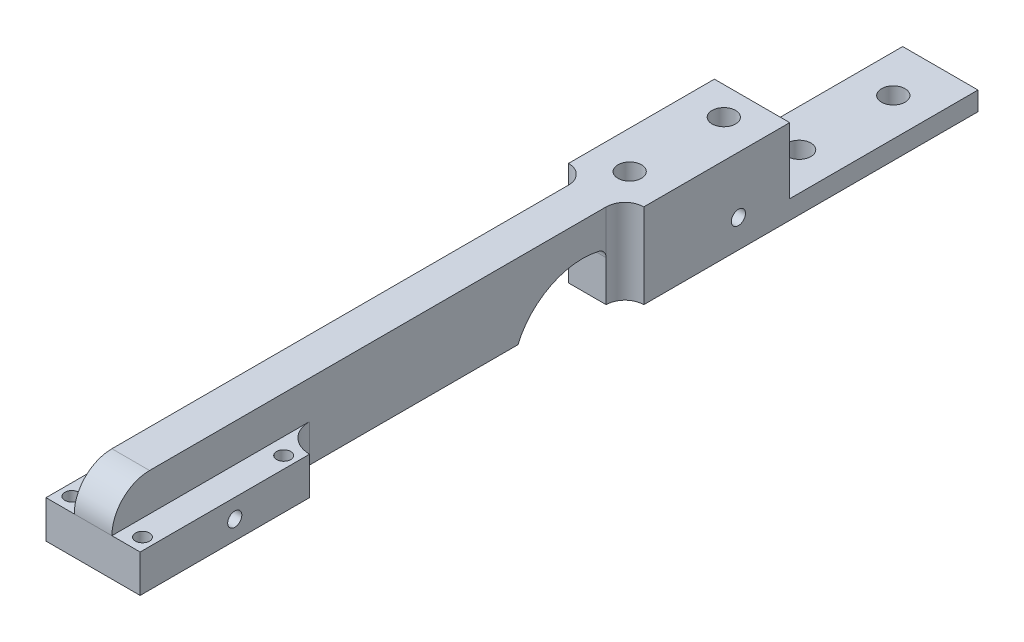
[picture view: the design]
ISO-10303-21;
HEADER;
FILE_DESCRIPTION(('STEP AP214'),'2;1');
FILE_NAME('part.step','',(''),(''),'','','');
FILE_SCHEMA(('AUTOMOTIVE_DESIGN { 1 0 10303 214 1 1 1 1 }'));
ENDSEC;
DATA;
#1=APPLICATION_CONTEXT('core data for automotive mechanical design processes');
#2=APPLICATION_PROTOCOL_DEFINITION('international standard','automotive_design',2000,#1);
#3=PRODUCT_CONTEXT('',#1,'mechanical');
#4=PRODUCT('Part','Part','',(#3));
#5=PRODUCT_RELATED_PRODUCT_CATEGORY('part','',(#4));
#6=PRODUCT_DEFINITION_FORMATION('','',#4);
#7=PRODUCT_DEFINITION_CONTEXT('part definition',#1,'design');
#8=PRODUCT_DEFINITION('design','',#6,#7);
#9=PRODUCT_DEFINITION_SHAPE('','',#8);
#10=(LENGTH_UNIT() NAMED_UNIT(*) SI_UNIT(.MILLI.,.METRE.));
#11=(NAMED_UNIT(*) PLANE_ANGLE_UNIT() SI_UNIT($,.RADIAN.));
#12=(NAMED_UNIT(*) SI_UNIT($,.STERADIAN.) SOLID_ANGLE_UNIT());
#13=UNCERTAINTY_MEASURE_WITH_UNIT(LENGTH_MEASURE(1.E-05),#10,'distance_accuracy_value','');
#14=(GEOMETRIC_REPRESENTATION_CONTEXT(3) GLOBAL_UNCERTAINTY_ASSIGNED_CONTEXT((#13)) GLOBAL_UNIT_ASSIGNED_CONTEXT((#10,
#11,#12)) REPRESENTATION_CONTEXT('',''));
#15=CARTESIAN_POINT('',(0.,0.,0.));
#16=DIRECTION('',(0.,0.,1.));
#17=DIRECTION('',(1.,0.,0.));
#18=AXIS2_PLACEMENT_3D('',#15,#16,#17);
#19=CARTESIAN_POINT('',(0.,0.,0.));
#20=DIRECTION('',(0.,0.,1.));
#21=DIRECTION('',(1.,0.,0.));
#22=AXIS2_PLACEMENT_3D('',#19,#20,#21);
#23=PLANE('',#22);
#24=DIRECTION('',(1.,0.,0.));
#25=VECTOR('',#24,1.);
#26=CARTESIAN_POINT('',(-8.,0.,0.));
#27=LINE('',#26,#25);
#28=CARTESIAN_POINT('',(-8.,0.,0.));
#29=VERTEX_POINT('',#28);
#30=CARTESIAN_POINT('',(8.,0.,0.));
#31=VERTEX_POINT('',#30);
#32=EDGE_CURVE('E338',#29,#31,#27,.T.);
#33=ORIENTED_EDGE('',*,*,#32,.F.);
#34=DIRECTION('',(0.,1.,0.));
#35=VECTOR('',#34,1.);
#36=CARTESIAN_POINT('',(-8.,-4.,0.));
#37=LINE('',#36,#35);
#38=CARTESIAN_POINT('',(-8.,14.,0.));
#39=VERTEX_POINT('',#38);
#40=EDGE_CURVE('E562',#29,#39,#37,.T.);
#41=ORIENTED_EDGE('',*,*,#40,.T.);
#42=DIRECTION('',(-1.,0.,0.));
#43=VECTOR('',#42,1.);
#44=CARTESIAN_POINT('',(4.,14.,0.));
#45=LINE('',#44,#43);
#46=CARTESIAN_POINT('',(8.,14.,0.));
#47=VERTEX_POINT('',#46);
#48=EDGE_CURVE('E549',#47,#39,#45,.T.);
#49=ORIENTED_EDGE('',*,*,#48,.F.);
#50=DIRECTION('',(0.,1.,0.));
#51=VECTOR('',#50,1.);
#52=CARTESIAN_POINT('',(8.,-4.,0.));
#53=LINE('',#52,#51);
#54=EDGE_CURVE('E359',#31,#47,#53,.T.);
#55=ORIENTED_EDGE('',*,*,#54,.F.);
#56=EDGE_LOOP('',(#33,#41,#49,#55));
#57=FACE_BOUND('',#56,.T.);
#58=ADVANCED_FACE('F33',(#57),#23,.F.);
#59=CARTESIAN_POINT('',(10.,-2.,140.));
#60=DIRECTION('',(0.,1.,0.));
#61=DIRECTION('',(-1.,0.,0.));
#62=AXIS2_PLACEMENT_3D('',#59,#60,#61);
#63=PLANE('',#62);
#64=DIRECTION('',(0.,0.,-1.));
#65=VECTOR('',#64,1.);
#66=CARTESIAN_POINT('',(-3.,-2.,79.));
#67=LINE('',#66,#65);
#68=CARTESIAN_POINT('',(-3.,-2.,79.));
#69=VERTEX_POINT('',#68);
#70=CARTESIAN_POINT('',(-3.,-2.,65.));
#71=VERTEX_POINT('',#70);
#72=EDGE_CURVE('E268',#69,#71,#67,.T.);
#73=ORIENTED_EDGE('',*,*,#72,.F.);
#74=CARTESIAN_POINT('',(0.,-2.,79.));
#75=DIRECTION('',(0.,-1.,0.));
#76=DIRECTION('',(1.,0.,0.));
#77=AXIS2_PLACEMENT_3D('',#74,#75,#76);
#78=CIRCLE('',#77,3.);
#79=CARTESIAN_POINT('',(3.,-2.,79.));
#80=VERTEX_POINT('',#79);
#81=EDGE_CURVE('E48',#80,#69,#78,.T.);
#82=ORIENTED_EDGE('',*,*,#81,.F.);
#83=DIRECTION('',(0.,0.,1.));
#84=VECTOR('',#83,1.);
#85=CARTESIAN_POINT('',(3.,-2.,79.));
#86=LINE('',#85,#84);
#87=CARTESIAN_POINT('',(3.,-2.,65.));
#88=VERTEX_POINT('',#87);
#89=EDGE_CURVE('E256',#88,#80,#86,.T.);
#90=ORIENTED_EDGE('',*,*,#89,.F.);
#91=CARTESIAN_POINT('',(0.,-2.,65.));
#92=DIRECTION('',(0.,-1.,0.));
#93=DIRECTION('',(1.,0.,0.));
#94=AXIS2_PLACEMENT_3D('',#91,#92,#93);
#95=CIRCLE('',#94,3.);
#96=EDGE_CURVE('E259',#71,#88,#95,.T.);
#97=ORIENTED_EDGE('',*,*,#96,.F.);
#98=EDGE_LOOP('',(#73,#82,#90,#97));
#99=FACE_BOUND('',#98,.T.);
#100=CARTESIAN_POINT('',(-7.49999999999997,-2.,107.));
#101=DIRECTION('',(0.,1.,0.));
#102=DIRECTION('',(-1.,0.,0.));
#103=AXIS2_PLACEMENT_3D('',#100,#101,#102);
#104=CIRCLE('',#103,1.5);
#105=CARTESIAN_POINT('',(-5.99999999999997,-2.,107.));
#106=VERTEX_POINT('',#105);
#107=CARTESIAN_POINT('',(-7.5,-2.,108.5));
#108=VERTEX_POINT('',#107);
#109=EDGE_CURVE('E323',#106,#108,#104,.T.);
#110=ORIENTED_EDGE('',*,*,#109,.T.);
#111=DIRECTION('',(0.,0.,-1.));
#112=VECTOR('',#111,1.);
#113=CARTESIAN_POINT('',(-7.5,-2.,137.));
#114=LINE('',#113,#112);
#115=CARTESIAN_POINT('',(-7.5,-2.,135.5));
#116=VERTEX_POINT('',#115);
#117=EDGE_CURVE('E275',#116,#108,#114,.T.);
#118=ORIENTED_EDGE('',*,*,#117,.F.);
#119=CARTESIAN_POINT('',(-7.5,-2.,137.));
#120=DIRECTION('',(0.,1.,0.));
#121=DIRECTION('',(-1.,0.,0.));
#122=AXIS2_PLACEMENT_3D('',#119,#120,#121);
#123=CIRCLE('',#122,1.5);
#124=CARTESIAN_POINT('',(-6.,-2.,137.));
#125=VERTEX_POINT('',#124);
#126=EDGE_CURVE('E317',#116,#125,#123,.T.);
#127=ORIENTED_EDGE('',*,*,#126,.T.);
#128=DIRECTION('',(-1.,0.,0.));
#129=VECTOR('',#128,1.);
#130=CARTESIAN_POINT('',(-7.5,-2.,137.));
#131=LINE('',#130,#129);
#132=CARTESIAN_POINT('',(6.,-2.,137.));
#133=VERTEX_POINT('',#132);
#134=EDGE_CURVE('E283',#133,#125,#131,.T.);
#135=ORIENTED_EDGE('',*,*,#134,.F.);
#136=CARTESIAN_POINT('',(7.5,-2.,137.));
#137=DIRECTION('',(0.,1.,0.));
#138=DIRECTION('',(-1.,0.,0.));
#139=AXIS2_PLACEMENT_3D('',#136,#137,#138);
#140=CIRCLE('',#139,1.5);
#141=CARTESIAN_POINT('',(7.5,-2.,135.5));
#142=VERTEX_POINT('',#141);
#143=EDGE_CURVE('E335',#133,#142,#140,.T.);
#144=ORIENTED_EDGE('',*,*,#143,.T.);
#145=DIRECTION('',(0.,0.,1.));
#146=VECTOR('',#145,1.);
#147=CARTESIAN_POINT('',(7.5,-2.,137.));
#148=LINE('',#147,#146);
#149=CARTESIAN_POINT('',(7.5,-2.,108.5));
#150=VERTEX_POINT('',#149);
#151=EDGE_CURVE('E294',#150,#142,#148,.T.);
#152=ORIENTED_EDGE('',*,*,#151,.F.);
#153=CARTESIAN_POINT('',(7.5,-2.,107.));
#154=DIRECTION('',(0.,1.,0.));
#155=DIRECTION('',(-1.,0.,0.));
#156=AXIS2_PLACEMENT_3D('',#153,#154,#155);
#157=CIRCLE('',#156,1.5);
#158=CARTESIAN_POINT('',(6.,-2.,107.));
#159=VERTEX_POINT('',#158);
#160=EDGE_CURVE('E329',#150,#159,#157,.T.);
#161=ORIENTED_EDGE('',*,*,#160,.T.);
#162=DIRECTION('',(1.,0.,0.));
#163=VECTOR('',#162,1.);
#164=CARTESIAN_POINT('',(-7.5,-2.,107.));
#165=LINE('',#164,#163);
#166=EDGE_CURVE('E292',#106,#159,#165,.T.);
#167=ORIENTED_EDGE('',*,*,#166,.F.);
#168=EDGE_LOOP('',(#110,#118,#127,#135,#144,#152,#161,#167));
#169=FACE_BOUND('',#168,.T.);
#170=DIRECTION('',(0.,0.,-1.));
#171=VECTOR('',#170,1.);
#172=CARTESIAN_POINT('',(-4.,-2.,0.));
#173=LINE('',#172,#171);
#174=CARTESIAN_POINT('',(-3.99999999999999,-2.,98.));
#175=VERTEX_POINT('',#174);
#176=CARTESIAN_POINT('',(-4.,-1.99999999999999,53.7477270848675));
#177=VERTEX_POINT('',#176);
#178=EDGE_CURVE('E528',#175,#177,#173,.T.);
#179=ORIENTED_EDGE('',*,*,#178,.T.);
#180=DIRECTION('',(1.,0.,0.));
#181=VECTOR('',#180,1.);
#182=CARTESIAN_POINT('',(-10.000025,-1.99999999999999,53.7477270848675));
#183=LINE('',#182,#181);
#184=CARTESIAN_POINT('',(4.,-1.99999999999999,53.7477270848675));
#185=VERTEX_POINT('',#184);
#186=EDGE_CURVE('E579',#177,#185,#183,.T.);
#187=ORIENTED_EDGE('',*,*,#186,.T.);
#188=DIRECTION('',(0.,0.,1.));
#189=VECTOR('',#188,1.);
#190=CARTESIAN_POINT('',(4.,-2.,0.));
#191=LINE('',#190,#189);
#192=CARTESIAN_POINT('',(4.00000000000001,-2.,98.));
#193=VERTEX_POINT('',#192);
#194=EDGE_CURVE('E518',#185,#193,#191,.T.);
#195=ORIENTED_EDGE('',*,*,#194,.T.);
#196=CARTESIAN_POINT('',(10.,-2.,98.));
#197=DIRECTION('',(0.,1.,0.));
#198=DIRECTION('',(0.,0.,1.));
#199=AXIS2_PLACEMENT_3D('',#196,#197,#198);
#200=CIRCLE('',#199,6.);
#201=CARTESIAN_POINT('',(10.,-2.,104.));
#202=VERTEX_POINT('',#201);
#203=EDGE_CURVE('E521',#193,#202,#200,.T.);
#204=ORIENTED_EDGE('',*,*,#203,.T.);
#205=DIRECTION('',(0.,0.,-1.));
#206=VECTOR('',#205,1.);
#207=CARTESIAN_POINT('',(10.,-2.,140.));
#208=LINE('',#207,#206);
#209=CARTESIAN_POINT('',(10.,-2.,140.));
#210=VERTEX_POINT('',#209);
#211=EDGE_CURVE('E500',#210,#202,#208,.T.);
#212=ORIENTED_EDGE('',*,*,#211,.F.);
#213=DIRECTION('',(1.,0.,0.));
#214=VECTOR('',#213,1.);
#215=CARTESIAN_POINT('',(10.,-2.,140.));
#216=LINE('',#215,#214);
#217=CARTESIAN_POINT('',(-10.,-2.,140.));
#218=VERTEX_POINT('',#217);
#219=EDGE_CURVE('E487',#218,#210,#216,.T.);
#220=ORIENTED_EDGE('',*,*,#219,.F.);
#221=DIRECTION('',(0.,0.,-1.));
#222=VECTOR('',#221,1.);
#223=CARTESIAN_POINT('',(-10.,-2.,140.));
#224=LINE('',#223,#222);
#225=CARTESIAN_POINT('',(-9.99999999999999,-2.,104.));
#226=VERTEX_POINT('',#225);
#227=EDGE_CURVE('E503',#218,#226,#224,.T.);
#228=ORIENTED_EDGE('',*,*,#227,.T.);
#229=CARTESIAN_POINT('',(-9.99999999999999,-2.,98.));
#230=DIRECTION('',(0.,1.,0.));
#231=DIRECTION('',(0.,0.,-1.));
#232=AXIS2_PLACEMENT_3D('',#229,#230,#231);
#233=CIRCLE('',#232,6.);
#234=EDGE_CURVE('E525',#226,#175,#233,.T.);
#235=ORIENTED_EDGE('',*,*,#234,.T.);
#236=EDGE_LOOP('',(#179,#187,#195,#204,#212,#220,#228,#235));
#237=FACE_BOUND('',#236,.T.);
#238=ADVANCED_FACE('F390',(#99,#169,#237),#63,.F.);
#239=CARTESIAN_POINT('',(10.,6.,140.));
#240=DIRECTION('',(0.,-1.,0.));
#241=DIRECTION('',(1.,0.,0.));
#242=AXIS2_PLACEMENT_3D('',#239,#240,#241);
#243=PLANE('',#242);
#244=CARTESIAN_POINT('',(7.5,6.,107.));
#245=DIRECTION('',(0.,1.,0.));
#246=DIRECTION('',(0.,0.,1.));
#247=AXIS2_PLACEMENT_3D('',#244,#245,#246);
#248=CIRCLE('',#247,1.5);
#249=CARTESIAN_POINT('',(7.5,6.,108.5));
#250=VERTEX_POINT('',#249);
#251=EDGE_CURVE('E326',#250,#250,#248,.T.);
#252=ORIENTED_EDGE('',*,*,#251,.F.);
#253=EDGE_LOOP('',(#252));
#254=FACE_BOUND('',#253,.T.);
#255=CARTESIAN_POINT('',(7.5,6.,137.));
#256=DIRECTION('',(0.,1.,0.));
#257=DIRECTION('',(0.,0.,1.));
#258=AXIS2_PLACEMENT_3D('',#255,#256,#257);
#259=CIRCLE('',#258,1.5);
#260=CARTESIAN_POINT('',(7.5,6.,138.5));
#261=VERTEX_POINT('',#260);
#262=EDGE_CURVE('E332',#261,#261,#259,.T.);
#263=ORIENTED_EDGE('',*,*,#262,.F.);
#264=EDGE_LOOP('',(#263));
#265=FACE_BOUND('',#264,.T.);
#266=DIRECTION('',(0.,0.,-1.));
#267=VECTOR('',#266,1.);
#268=CARTESIAN_POINT('',(4.,6.,140.));
#269=LINE('',#268,#267);
#270=CARTESIAN_POINT('',(4.,6.,140.));
#271=VERTEX_POINT('',#270);
#272=CARTESIAN_POINT('',(4.00000000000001,6.,98.));
#273=VERTEX_POINT('',#272);
#274=EDGE_CURVE('E465',#271,#273,#269,.T.);
#275=ORIENTED_EDGE('',*,*,#274,.F.);
#276=DIRECTION('',(-1.,0.,0.));
#277=VECTOR('',#276,1.);
#278=CARTESIAN_POINT('',(10.,6.,140.));
#279=LINE('',#278,#277);
#280=CARTESIAN_POINT('',(10.,6.,140.));
#281=VERTEX_POINT('',#280);
#282=EDGE_CURVE('E468',#281,#271,#279,.T.);
#283=ORIENTED_EDGE('',*,*,#282,.F.);
#284=DIRECTION('',(0.,0.,-1.));
#285=VECTOR('',#284,1.);
#286=CARTESIAN_POINT('',(10.,6.,140.));
#287=LINE('',#286,#285);
#288=CARTESIAN_POINT('',(10.,6.,104.));
#289=VERTEX_POINT('',#288);
#290=EDGE_CURVE('E375',#281,#289,#287,.T.);
#291=ORIENTED_EDGE('',*,*,#290,.T.);
#292=CARTESIAN_POINT('',(10.,6.,98.));
#293=DIRECTION('',(0.,1.,0.));
#294=DIRECTION('',(0.,0.,1.));
#295=AXIS2_PLACEMENT_3D('',#292,#293,#294);
#296=CIRCLE('',#295,6.);
#297=EDGE_CURVE('E470',#273,#289,#296,.T.);
#298=ORIENTED_EDGE('',*,*,#297,.F.);
#299=EDGE_LOOP('',(#275,#283,#291,#298));
#300=FACE_BOUND('',#299,.T.);
#301=ADVANCED_FACE('F435',(#254,#265,#300),#243,.F.);
#302=CARTESIAN_POINT('',(10.,-2.,140.));
#303=DIRECTION('',(-1.,0.,0.));
#304=DIRECTION('',(0.,0.,1.));
#305=AXIS2_PLACEMENT_3D('',#302,#303,#304);
#306=PLANE('',#305);
#307=CARTESIAN_POINT('',(10.,2.,119.9));
#308=DIRECTION('',(1.,0.,0.));
#309=DIRECTION('',(0.,0.,-1.));
#310=AXIS2_PLACEMENT_3D('',#307,#308,#309);
#311=CIRCLE('',#310,1.5);
#312=CARTESIAN_POINT('',(10.,2.,118.4));
#313=VERTEX_POINT('',#312);
#314=EDGE_CURVE('E1008',#313,#313,#311,.T.);
#315=ORIENTED_EDGE('',*,*,#314,.F.);
#316=EDGE_LOOP('',(#315));
#317=FACE_BOUND('',#316,.T.);
#318=ORIENTED_EDGE('',*,*,#211,.T.);
#319=DIRECTION('',(0.,1.,0.));
#320=VECTOR('',#319,1.);
#321=CARTESIAN_POINT('',(10.,-2.,104.));
#322=LINE('',#321,#320);
#323=EDGE_CURVE('E512',#202,#289,#322,.T.);
#324=ORIENTED_EDGE('',*,*,#323,.T.);
#325=ORIENTED_EDGE('',*,*,#290,.F.);
#326=DIRECTION('',(0.,1.,0.));
#327=VECTOR('',#326,1.);
#328=CARTESIAN_POINT('',(10.,-2.,140.));
#329=LINE('',#328,#327);
#330=EDGE_CURVE('E482',#210,#281,#329,.T.);
#331=ORIENTED_EDGE('',*,*,#330,.F.);
#332=EDGE_LOOP('',(#318,#324,#325,#331));
#333=FACE_BOUND('',#332,.T.);
#334=ADVANCED_FACE('F35',(#317,#333),#306,.F.);
#335=CARTESIAN_POINT('',(-7.5,6.,137.));
#336=DIRECTION('',(0.,1.,0.));
#337=DIRECTION('',(0.,0.,-1.));
#338=AXIS2_PLACEMENT_3D('',#335,#336,#337);
#339=CIRCLE('',#338,1.5);
#340=CARTESIAN_POINT('',(-7.5,6.,135.5));
#341=VERTEX_POINT('',#340);
#342=EDGE_CURVE('E314',#341,#341,#339,.T.);
#343=ORIENTED_EDGE('',*,*,#342,.F.);
#344=EDGE_LOOP('',(#343));
#345=FACE_BOUND('',#344,.T.);
#346=CARTESIAN_POINT('',(-7.49999999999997,6.,107.));
#347=DIRECTION('',(0.,1.,0.));
#348=DIRECTION('',(0.,0.,-1.));
#349=AXIS2_PLACEMENT_3D('',#346,#347,#348);
#350=CIRCLE('',#349,1.5);
#351=CARTESIAN_POINT('',(-7.49999999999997,6.,105.5));
#352=VERTEX_POINT('',#351);
#353=EDGE_CURVE('E320',#352,#352,#350,.T.);
#354=ORIENTED_EDGE('',*,*,#353,.F.);
#355=EDGE_LOOP('',(#354));
#356=FACE_BOUND('',#355,.T.);
#357=CARTESIAN_POINT('',(-4.,6.,140.));
#358=VERTEX_POINT('',#357);
#359=CARTESIAN_POINT('',(-10.,6.,140.));
#360=VERTEX_POINT('',#359);
#361=EDGE_CURVE('E485',#358,#360,#279,.T.);
#362=ORIENTED_EDGE('',*,*,#361,.F.);
#363=DIRECTION('',(0.,0.,-1.));
#364=VECTOR('',#363,1.);
#365=CARTESIAN_POINT('',(-4.,6.,140.));
#366=LINE('',#365,#364);
#367=CARTESIAN_POINT('',(-4.,6.,98.));
#368=VERTEX_POINT('',#367);
#369=EDGE_CURVE('E555',#358,#368,#366,.T.);
#370=ORIENTED_EDGE('',*,*,#369,.T.);
#371=CARTESIAN_POINT('',(-9.99999999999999,6.,98.));
#372=DIRECTION('',(0.,1.,0.));
#373=DIRECTION('',(0.,0.,-1.));
#374=AXIS2_PLACEMENT_3D('',#371,#372,#373);
#375=CIRCLE('',#374,6.);
#376=CARTESIAN_POINT('',(-9.99999999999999,6.,104.));
#377=VERTEX_POINT('',#376);
#378=EDGE_CURVE('E520',#377,#368,#375,.T.);
#379=ORIENTED_EDGE('',*,*,#378,.F.);
#380=DIRECTION('',(0.,0.,-1.));
#381=VECTOR('',#380,1.);
#382=CARTESIAN_POINT('',(-10.,6.,140.));
#383=LINE('',#382,#381);
#384=EDGE_CURVE('E505',#360,#377,#383,.T.);
#385=ORIENTED_EDGE('',*,*,#384,.F.);
#386=EDGE_LOOP('',(#362,#370,#379,#385));
#387=FACE_BOUND('',#386,.T.);
#388=ADVANCED_FACE('F444',(#345,#356,#387),#243,.F.);
#389=CARTESIAN_POINT('',(-10.,-2.,140.));
#390=DIRECTION('',(1.,0.,0.));
#391=DIRECTION('',(0.,0.,-1.));
#392=AXIS2_PLACEMENT_3D('',#389,#390,#391);
#393=PLANE('',#392);
#394=ORIENTED_EDGE('',*,*,#384,.T.);
#395=DIRECTION('',(0.,1.,0.));
#396=VECTOR('',#395,1.);
#397=CARTESIAN_POINT('',(-9.99999999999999,-2.,104.));
#398=LINE('',#397,#396);
#399=EDGE_CURVE('E530',#226,#377,#398,.T.);
#400=ORIENTED_EDGE('',*,*,#399,.F.);
#401=ORIENTED_EDGE('',*,*,#227,.F.);
#402=DIRECTION('',(0.,-1.,0.));
#403=VECTOR('',#402,1.);
#404=CARTESIAN_POINT('',(-10.,-2.,140.));
#405=LINE('',#404,#403);
#406=EDGE_CURVE('E484',#360,#218,#405,.T.);
#407=ORIENTED_EDGE('',*,*,#406,.F.);
#408=EDGE_LOOP('',(#394,#400,#401,#407));
#409=FACE_BOUND('',#408,.T.);
#410=ADVANCED_FACE('F442',(#409),#393,.F.);
#411=CARTESIAN_POINT('',(0.,0.,140.));
#412=DIRECTION('',(0.,0.,1.));
#413=DIRECTION('',(1.,0.,0.));
#414=AXIS2_PLACEMENT_3D('',#411,#412,#413);
#415=PLANE('',#414);
#416=ORIENTED_EDGE('',*,*,#330,.T.);
#417=ORIENTED_EDGE('',*,*,#282,.T.);
#418=DIRECTION('',(-1.,0.,0.));
#419=VECTOR('',#418,1.);
#420=CARTESIAN_POINT('',(4.,6.,140.));
#421=LINE('',#420,#419);
#422=EDGE_CURVE('E480',#271,#358,#421,.T.);
#423=ORIENTED_EDGE('',*,*,#422,.T.);
#424=ORIENTED_EDGE('',*,*,#361,.T.);
#425=ORIENTED_EDGE('',*,*,#406,.T.);
#426=ORIENTED_EDGE('',*,*,#219,.T.);
#427=EDGE_LOOP('',(#416,#417,#423,#424,#425,#426));
#428=FACE_BOUND('',#427,.T.);
#429=ADVANCED_FACE('F439',(#428),#415,.T.);
#430=CARTESIAN_POINT('',(-4.,-2.,0.));
#431=DIRECTION('',(1.,0.,0.));
#432=DIRECTION('',(0.,0.,-1.));
#433=AXIS2_PLACEMENT_3D('',#430,#431,#432);
#434=PLANE('',#433);
#435=DIRECTION('',(0.,0.,1.));
#436=VECTOR('',#435,1.);
#437=CARTESIAN_POINT('',(-4.,14.,132.));
#438=LINE('',#437,#436);
#439=CARTESIAN_POINT('',(-4.,14.,35.));
#440=VERTEX_POINT('',#439);
#441=CARTESIAN_POINT('',(-4.,14.,132.));
#442=VERTEX_POINT('',#441);
#443=EDGE_CURVE('E560',#440,#442,#438,.T.);
#444=ORIENTED_EDGE('',*,*,#443,.F.);
#445=DIRECTION('',(0.,1.,0.));
#446=VECTOR('',#445,1.);
#447=CARTESIAN_POINT('',(-4.,-4.,35.));
#448=LINE('',#447,#446);
#449=CARTESIAN_POINT('',(-4.,4.64911064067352,35.));
#450=VERTEX_POINT('',#449);
#451=EDGE_CURVE('E612',#450,#440,#448,.T.);
#452=ORIENTED_EDGE('',*,*,#451,.F.);
#453=CARTESIAN_POINT('',(-4.,4.64911064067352,37.));
#454=DIRECTION('',(1.,0.,0.));
#455=DIRECTION('',(0.,0.,-1.));
#456=AXIS2_PLACEMENT_3D('',#453,#454,#455);
#457=CIRCLE('',#456,2.);
#458=CARTESIAN_POINT('',(-4.,6.5951276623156,36.5384615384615));
#459=VERTEX_POINT('',#458);
#460=EDGE_CURVE('E588',#450,#459,#457,.T.);
#461=ORIENTED_EDGE('',*,*,#460,.T.);
#462=CARTESIAN_POINT('',(-4.,-8.,40.));
#463=DIRECTION('',(1.,0.,0.));
#464=DIRECTION('',(0.,0.,-1.));
#465=AXIS2_PLACEMENT_3D('',#462,#463,#464);
#466=CIRCLE('',#465,15.);
#467=EDGE_CURVE('E556',#459,#177,#466,.T.);
#468=ORIENTED_EDGE('',*,*,#467,.T.);
#469=ORIENTED_EDGE('',*,*,#178,.F.);
#470=DIRECTION('',(0.,1.,0.));
#471=VECTOR('',#470,1.);
#472=CARTESIAN_POINT('',(-3.99999999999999,-2.,98.));
#473=LINE('',#472,#471);
#474=EDGE_CURVE('E531',#175,#368,#473,.T.);
#475=ORIENTED_EDGE('',*,*,#474,.T.);
#476=ORIENTED_EDGE('',*,*,#369,.F.);
#477=CARTESIAN_POINT('',(-4.,6.,132.));
#478=DIRECTION('',(1.,0.,0.));
#479=DIRECTION('',(0.,0.,1.));
#480=AXIS2_PLACEMENT_3D('',#477,#478,#479);
#481=CIRCLE('',#480,8.);
#482=EDGE_CURVE('E552',#442,#358,#481,.T.);
#483=ORIENTED_EDGE('',*,*,#482,.F.);
#484=EDGE_LOOP('',(#444,#452,#461,#468,#469,#475,#476,#483));
#485=FACE_BOUND('',#484,.T.);
#486=ADVANCED_FACE('F608',(#485),#434,.F.);
#487=CARTESIAN_POINT('',(-9.99999999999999,-2.,98.));
#488=DIRECTION('',(0.,1.,0.));
#489=DIRECTION('',(0.,0.,1.));
#490=AXIS2_PLACEMENT_3D('',#487,#488,#489);
#491=CYLINDRICAL_SURFACE('',#490,6.);
#492=ORIENTED_EDGE('',*,*,#378,.T.);
#493=ORIENTED_EDGE('',*,*,#474,.F.);
#494=ORIENTED_EDGE('',*,*,#234,.F.);
#495=ORIENTED_EDGE('',*,*,#399,.T.);
#496=EDGE_LOOP('',(#492,#493,#494,#495));
#497=FACE_BOUND('',#496,.T.);
#498=ADVANCED_FACE('F697',(#497),#491,.F.);
#499=CARTESIAN_POINT('',(10.,-2.,98.));
#500=DIRECTION('',(0.,1.,0.));
#501=DIRECTION('',(0.,0.,1.));
#502=AXIS2_PLACEMENT_3D('',#499,#500,#501);
#503=CYLINDRICAL_SURFACE('',#502,6.);
#504=ORIENTED_EDGE('',*,*,#297,.T.);
#505=ORIENTED_EDGE('',*,*,#323,.F.);
#506=ORIENTED_EDGE('',*,*,#203,.F.);
#507=DIRECTION('',(0.,1.,0.));
#508=VECTOR('',#507,1.);
#509=CARTESIAN_POINT('',(4.00000000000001,-2.,98.));
#510=LINE('',#509,#508);
#511=EDGE_CURVE('E517',#193,#273,#510,.T.);
#512=ORIENTED_EDGE('',*,*,#511,.T.);
#513=EDGE_LOOP('',(#504,#505,#506,#512));
#514=FACE_BOUND('',#513,.T.);
#515=ADVANCED_FACE('F600',(#514),#503,.F.);
#516=CARTESIAN_POINT('',(4.,-2.,0.));
#517=DIRECTION('',(-1.,0.,0.));
#518=DIRECTION('',(0.,0.,1.));
#519=AXIS2_PLACEMENT_3D('',#516,#517,#518);
#520=PLANE('',#519);
#521=CARTESIAN_POINT('',(4.,4.64911064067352,37.));
#522=DIRECTION('',(1.,0.,0.));
#523=DIRECTION('',(0.,0.,-1.));
#524=AXIS2_PLACEMENT_3D('',#521,#522,#523);
#525=CIRCLE('',#524,2.);
#526=CARTESIAN_POINT('',(4.,4.64911064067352,35.));
#527=VERTEX_POINT('',#526);
#528=CARTESIAN_POINT('',(4.,6.5951276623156,36.5384615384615));
#529=VERTEX_POINT('',#528);
#530=EDGE_CURVE('E573',#527,#529,#525,.T.);
#531=ORIENTED_EDGE('',*,*,#530,.F.);
#532=DIRECTION('',(0.,1.,0.));
#533=VECTOR('',#532,1.);
#534=CARTESIAN_POINT('',(4.00000000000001,-4.,35.));
#535=LINE('',#534,#533);
#536=CARTESIAN_POINT('',(4.,14.,35.));
#537=VERTEX_POINT('',#536);
#538=EDGE_CURVE('E616',#527,#537,#535,.T.);
#539=ORIENTED_EDGE('',*,*,#538,.T.);
#540=DIRECTION('',(0.,0.,1.));
#541=VECTOR('',#540,1.);
#542=CARTESIAN_POINT('',(4.,14.,132.));
#543=LINE('',#542,#541);
#544=CARTESIAN_POINT('',(4.,14.,132.));
#545=VERTEX_POINT('',#544);
#546=EDGE_CURVE('E474',#537,#545,#543,.T.);
#547=ORIENTED_EDGE('',*,*,#546,.T.);
#548=CARTESIAN_POINT('',(4.,6.,132.));
#549=DIRECTION('',(1.,0.,0.));
#550=DIRECTION('',(0.,0.,1.));
#551=AXIS2_PLACEMENT_3D('',#548,#549,#550);
#552=CIRCLE('',#551,8.);
#553=EDGE_CURVE('E475',#545,#271,#552,.T.);
#554=ORIENTED_EDGE('',*,*,#553,.T.);
#555=ORIENTED_EDGE('',*,*,#274,.T.);
#556=ORIENTED_EDGE('',*,*,#511,.F.);
#557=ORIENTED_EDGE('',*,*,#194,.F.);
#558=CARTESIAN_POINT('',(4.,-8.,40.));
#559=DIRECTION('',(1.,0.,0.));
#560=DIRECTION('',(0.,0.,-1.));
#561=AXIS2_PLACEMENT_3D('',#558,#559,#560);
#562=CIRCLE('',#561,15.);
#563=EDGE_CURVE('E576',#529,#185,#562,.T.);
#564=ORIENTED_EDGE('',*,*,#563,.F.);
#565=EDGE_LOOP('',(#531,#539,#547,#554,#555,#556,#557,#564));
#566=FACE_BOUND('',#565,.T.);
#567=ADVANCED_FACE('F603',(#566),#520,.F.);
#568=CARTESIAN_POINT('',(4.,6.,132.));
#569=DIRECTION('',(-1.,0.,0.));
#570=DIRECTION('',(0.,0.,1.));
#571=AXIS2_PLACEMENT_3D('',#568,#569,#570);
#572=CYLINDRICAL_SURFACE('',#571,8.);
#573=ORIENTED_EDGE('',*,*,#482,.T.);
#574=ORIENTED_EDGE('',*,*,#422,.F.);
#575=ORIENTED_EDGE('',*,*,#553,.F.);
#576=DIRECTION('',(-1.,0.,0.));
#577=VECTOR('',#576,1.);
#578=CARTESIAN_POINT('',(4.,14.,132.));
#579=LINE('',#578,#577);
#580=EDGE_CURVE('E673',#545,#442,#579,.T.);
#581=ORIENTED_EDGE('',*,*,#580,.T.);
#582=EDGE_LOOP('',(#573,#574,#575,#581));
#583=FACE_BOUND('',#582,.T.);
#584=ADVANCED_FACE('F682',(#583),#572,.T.);
#585=CARTESIAN_POINT('',(4.,14.,132.));
#586=DIRECTION('',(0.,-1.,0.));
#587=DIRECTION('',(0.,0.,-1.));
#588=AXIS2_PLACEMENT_3D('',#585,#586,#587);
#589=PLANE('',#588);
#590=CARTESIAN_POINT('',(0.,14.,6.00000000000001));
#591=DIRECTION('',(0.,1.,0.));
#592=DIRECTION('',(0.,0.,1.));
#593=AXIS2_PLACEMENT_3D('',#590,#591,#592);
#594=CIRCLE('',#593,2.5);
#595=CARTESIAN_POINT('',(0.,14.,8.50000000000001));
#596=VERTEX_POINT('',#595);
#597=EDGE_CURVE('E1029',#596,#596,#594,.T.);
#598=ORIENTED_EDGE('',*,*,#597,.F.);
#599=EDGE_LOOP('',(#598));
#600=FACE_BOUND('',#599,.T.);
#601=CARTESIAN_POINT('',(0.,14.,26.));
#602=DIRECTION('',(0.,1.,0.));
#603=DIRECTION('',(0.,0.,1.));
#604=AXIS2_PLACEMENT_3D('',#601,#602,#603);
#605=CIRCLE('',#604,2.5);
#606=CARTESIAN_POINT('',(0.,14.,28.5));
#607=VERTEX_POINT('',#606);
#608=EDGE_CURVE('E262',#607,#607,#605,.T.);
#609=ORIENTED_EDGE('',*,*,#608,.F.);
#610=EDGE_LOOP('',(#609));
#611=FACE_BOUND('',#610,.T.);
#612=ORIENTED_EDGE('',*,*,#546,.F.);
#613=CARTESIAN_POINT('',(8.,14.,35.));
#614=DIRECTION('',(0.,-1.,0.));
#615=DIRECTION('',(0.,0.,-1.));
#616=AXIS2_PLACEMENT_3D('',#613,#614,#615);
#617=CIRCLE('',#616,4.);
#618=CARTESIAN_POINT('',(8.,14.,31.));
#619=VERTEX_POINT('',#618);
#620=EDGE_CURVE('E624',#537,#619,#617,.T.);
#621=ORIENTED_EDGE('',*,*,#620,.T.);
#622=DIRECTION('',(0.,0.,-1.));
#623=VECTOR('',#622,1.);
#624=CARTESIAN_POINT('',(8.,14.,0.));
#625=LINE('',#624,#623);
#626=EDGE_CURVE('E630',#619,#47,#625,.T.);
#627=ORIENTED_EDGE('',*,*,#626,.T.);
#628=ORIENTED_EDGE('',*,*,#48,.T.);
#629=DIRECTION('',(0.,0.,1.));
#630=VECTOR('',#629,1.);
#631=CARTESIAN_POINT('',(-8.,14.,0.));
#632=LINE('',#631,#630);
#633=CARTESIAN_POINT('',(-8.,14.,31.));
#634=VERTEX_POINT('',#633);
#635=EDGE_CURVE('E369',#39,#634,#632,.T.);
#636=ORIENTED_EDGE('',*,*,#635,.T.);
#637=CARTESIAN_POINT('',(-8.,14.,35.));
#638=DIRECTION('',(0.,-1.,0.));
#639=DIRECTION('',(0.,0.,1.));
#640=AXIS2_PLACEMENT_3D('',#637,#638,#639);
#641=CIRCLE('',#640,4.);
#642=EDGE_CURVE('E634',#634,#440,#641,.T.);
#643=ORIENTED_EDGE('',*,*,#642,.T.);
#644=ORIENTED_EDGE('',*,*,#443,.T.);
#645=ORIENTED_EDGE('',*,*,#580,.F.);
#646=EDGE_LOOP('',(#612,#621,#627,#628,#636,#643,#644,#645));
#647=FACE_BOUND('',#646,.T.);
#648=ADVANCED_FACE('F670',(#600,#611,#647),#589,.F.);
#649=CARTESIAN_POINT('',(-10.000025,-8.,40.));
#650=DIRECTION('',(1.,0.,0.));
#651=DIRECTION('',(0.,0.,-1.));
#652=AXIS2_PLACEMENT_3D('',#649,#650,#651);
#653=CYLINDRICAL_SURFACE('',#652,15.);
#654=DIRECTION('',(1.,0.,0.));
#655=VECTOR('',#654,1.);
#656=CARTESIAN_POINT('',(-10.000025,6.5951276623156,36.5384615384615));
#657=LINE('',#656,#655);
#658=EDGE_CURVE('E583',#459,#529,#657,.T.);
#659=ORIENTED_EDGE('',*,*,#658,.T.);
#660=ORIENTED_EDGE('',*,*,#563,.T.);
#661=ORIENTED_EDGE('',*,*,#186,.F.);
#662=ORIENTED_EDGE('',*,*,#467,.F.);
#663=EDGE_LOOP('',(#659,#660,#661,#662));
#664=FACE_BOUND('',#663,.T.);
#665=ADVANCED_FACE('F606',(#664),#653,.F.);
#666=CARTESIAN_POINT('',(-10.000025,4.64911064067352,37.));
#667=DIRECTION('',(1.,0.,0.));
#668=DIRECTION('',(0.,0.,-1.));
#669=AXIS2_PLACEMENT_3D('',#666,#667,#668);
#670=CYLINDRICAL_SURFACE('',#669,2.);
#671=DIRECTION('',(1.,0.,0.));
#672=VECTOR('',#671,1.);
#673=CARTESIAN_POINT('',(-10.000025,4.64911064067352,35.));
#674=LINE('',#673,#672);
#675=EDGE_CURVE('E578',#450,#527,#674,.T.);
#676=ORIENTED_EDGE('',*,*,#675,.T.);
#677=ORIENTED_EDGE('',*,*,#530,.T.);
#678=ORIENTED_EDGE('',*,*,#658,.F.);
#679=ORIENTED_EDGE('',*,*,#460,.F.);
#680=EDGE_LOOP('',(#676,#677,#678,#679));
#681=FACE_BOUND('',#680,.T.);
#682=ADVANCED_FACE('F614',(#681),#670,.F.);
#683=CARTESIAN_POINT('',(-10.000025,-2.,35.));
#684=DIRECTION('',(0.,0.,-1.));
#685=DIRECTION('',(-1.,0.,0.));
#686=AXIS2_PLACEMENT_3D('',#683,#684,#685);
#687=PLANE('',#686);
#688=DIRECTION('',(0.,1.,0.));
#689=VECTOR('',#688,1.);
#690=CARTESIAN_POINT('',(-4.,-2.,35.));
#691=LINE('',#690,#689);
#692=CARTESIAN_POINT('',(-4.,-4.,35.));
#693=VERTEX_POINT('',#692);
#694=EDGE_CURVE('E582',#693,#450,#691,.T.);
#695=ORIENTED_EDGE('',*,*,#694,.F.);
#696=DIRECTION('',(1.,0.,0.));
#697=VECTOR('',#696,1.);
#698=CARTESIAN_POINT('',(-4.,-4.,35.));
#699=LINE('',#698,#697);
#700=CARTESIAN_POINT('',(4.00000000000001,-4.,35.));
#701=VERTEX_POINT('',#700);
#702=EDGE_CURVE('E642',#693,#701,#699,.T.);
#703=ORIENTED_EDGE('',*,*,#702,.T.);
#704=DIRECTION('',(0.,1.,0.));
#705=VECTOR('',#704,1.);
#706=CARTESIAN_POINT('',(4.,-2.,35.));
#707=LINE('',#706,#705);
#708=EDGE_CURVE('E570',#701,#527,#707,.T.);
#709=ORIENTED_EDGE('',*,*,#708,.T.);
#710=ORIENTED_EDGE('',*,*,#675,.F.);
#711=EDGE_LOOP('',(#695,#703,#709,#710));
#712=FACE_BOUND('',#711,.T.);
#713=ADVANCED_FACE('F730',(#712),#687,.F.);
#714=CARTESIAN_POINT('',(8.,-4.,0.));
#715=DIRECTION('',(1.,0.,0.));
#716=DIRECTION('',(0.,0.,-1.));
#717=AXIS2_PLACEMENT_3D('',#714,#715,#716);
#718=PLANE('',#717);
#719=CARTESIAN_POINT('',(8.,2.,10.9));
#720=DIRECTION('',(1.,0.,0.));
#721=DIRECTION('',(0.,0.,-1.));
#722=AXIS2_PLACEMENT_3D('',#719,#720,#721);
#723=CIRCLE('',#722,1.5);
#724=CARTESIAN_POINT('',(8.,2.,9.40000000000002));
#725=VERTEX_POINT('',#724);
#726=EDGE_CURVE('E1009',#725,#725,#723,.T.);
#727=ORIENTED_EDGE('',*,*,#726,.F.);
#728=EDGE_LOOP('',(#727));
#729=FACE_BOUND('',#728,.T.);
#730=ORIENTED_EDGE('',*,*,#626,.F.);
#731=DIRECTION('',(0.,1.,0.));
#732=VECTOR('',#731,1.);
#733=CARTESIAN_POINT('',(8.,-4.,31.));
#734=LINE('',#733,#732);
#735=CARTESIAN_POINT('',(8.,-4.,31.));
#736=VERTEX_POINT('',#735);
#737=EDGE_CURVE('E625',#736,#619,#734,.T.);
#738=ORIENTED_EDGE('',*,*,#737,.F.);
#739=DIRECTION('',(0.,0.,-1.));
#740=VECTOR('',#739,1.);
#741=CARTESIAN_POINT('',(8.,-4.,0.));
#742=LINE('',#741,#740);
#743=CARTESIAN_POINT('',(8.,-4.,-40.));
#744=VERTEX_POINT('',#743);
#745=EDGE_CURVE('E565',#736,#744,#742,.T.);
#746=ORIENTED_EDGE('',*,*,#745,.T.);
#747=DIRECTION('',(0.,-1.,0.));
#748=VECTOR('',#747,1.);
#749=CARTESIAN_POINT('',(8.,-4.,-40.));
#750=LINE('',#749,#748);
#751=CARTESIAN_POINT('',(8.,0.,-40.));
#752=VERTEX_POINT('',#751);
#753=EDGE_CURVE('E344',#752,#744,#750,.T.);
#754=ORIENTED_EDGE('',*,*,#753,.F.);
#755=DIRECTION('',(0.,0.,1.));
#756=VECTOR('',#755,1.);
#757=CARTESIAN_POINT('',(8.,0.,-40.));
#758=LINE('',#757,#756);
#759=EDGE_CURVE('E350',#752,#31,#758,.T.);
#760=ORIENTED_EDGE('',*,*,#759,.T.);
#761=ORIENTED_EDGE('',*,*,#54,.T.);
#762=EDGE_LOOP('',(#730,#738,#746,#754,#760,#761));
#763=FACE_BOUND('',#762,.T.);
#764=ADVANCED_FACE('F666',(#729,#763),#718,.T.);
#765=CARTESIAN_POINT('',(8.,-4.,35.));
#766=DIRECTION('',(0.,1.,0.));
#767=DIRECTION('',(0.,0.,1.));
#768=AXIS2_PLACEMENT_3D('',#765,#766,#767);
#769=CYLINDRICAL_SURFACE('',#768,4.);
#770=ORIENTED_EDGE('',*,*,#620,.F.);
#771=ORIENTED_EDGE('',*,*,#538,.F.);
#772=ORIENTED_EDGE('',*,*,#708,.F.);
#773=CARTESIAN_POINT('',(8.,-4.,35.));
#774=DIRECTION('',(0.,-1.,0.));
#775=DIRECTION('',(0.,0.,-1.));
#776=AXIS2_PLACEMENT_3D('',#773,#774,#775);
#777=CIRCLE('',#776,4.);
#778=EDGE_CURVE('E640',#701,#736,#777,.T.);
#779=ORIENTED_EDGE('',*,*,#778,.T.);
#780=ORIENTED_EDGE('',*,*,#737,.T.);
#781=EDGE_LOOP('',(#770,#771,#772,#779,#780));
#782=FACE_BOUND('',#781,.T.);
#783=ADVANCED_FACE('F620',(#782),#769,.F.);
#784=CARTESIAN_POINT('',(-8.,-4.,35.));
#785=DIRECTION('',(0.,1.,0.));
#786=DIRECTION('',(0.,0.,1.));
#787=AXIS2_PLACEMENT_3D('',#784,#785,#786);
#788=CYLINDRICAL_SURFACE('',#787,4.);
#789=ORIENTED_EDGE('',*,*,#642,.F.);
#790=DIRECTION('',(0.,1.,0.));
#791=VECTOR('',#790,1.);
#792=CARTESIAN_POINT('',(-8.,-4.,31.));
#793=LINE('',#792,#791);
#794=CARTESIAN_POINT('',(-8.,-4.,31.));
#795=VERTEX_POINT('',#794);
#796=EDGE_CURVE('E564',#795,#634,#793,.T.);
#797=ORIENTED_EDGE('',*,*,#796,.F.);
#798=CARTESIAN_POINT('',(-8.,-4.,35.));
#799=DIRECTION('',(0.,-1.,0.));
#800=DIRECTION('',(0.,0.,1.));
#801=AXIS2_PLACEMENT_3D('',#798,#799,#800);
#802=CIRCLE('',#801,4.);
#803=EDGE_CURVE('E644',#795,#693,#802,.T.);
#804=ORIENTED_EDGE('',*,*,#803,.T.);
#805=ORIENTED_EDGE('',*,*,#694,.T.);
#806=ORIENTED_EDGE('',*,*,#451,.T.);
#807=EDGE_LOOP('',(#789,#797,#804,#805,#806));
#808=FACE_BOUND('',#807,.T.);
#809=ADVANCED_FACE('F753',(#808),#788,.F.);
#810=CARTESIAN_POINT('',(-8.,-4.,0.));
#811=DIRECTION('',(-1.,0.,0.));
#812=DIRECTION('',(0.,0.,1.));
#813=AXIS2_PLACEMENT_3D('',#810,#811,#812);
#814=PLANE('',#813);
#815=ORIENTED_EDGE('',*,*,#635,.F.);
#816=ORIENTED_EDGE('',*,*,#40,.F.);
#817=DIRECTION('',(0.,0.,1.));
#818=VECTOR('',#817,1.);
#819=CARTESIAN_POINT('',(-8.,0.,-40.));
#820=LINE('',#819,#818);
#821=CARTESIAN_POINT('',(-8.,0.,-40.));
#822=VERTEX_POINT('',#821);
#823=EDGE_CURVE('E364',#822,#29,#820,.T.);
#824=ORIENTED_EDGE('',*,*,#823,.F.);
#825=DIRECTION('',(0.,1.,0.));
#826=VECTOR('',#825,1.);
#827=CARTESIAN_POINT('',(-8.,-4.,-40.));
#828=LINE('',#827,#826);
#829=CARTESIAN_POINT('',(-8.,-4.,-40.));
#830=VERTEX_POINT('',#829);
#831=EDGE_CURVE('E339',#830,#822,#828,.T.);
#832=ORIENTED_EDGE('',*,*,#831,.F.);
#833=DIRECTION('',(0.,0.,1.));
#834=VECTOR('',#833,1.);
#835=CARTESIAN_POINT('',(-8.,-4.,0.));
#836=LINE('',#835,#834);
#837=EDGE_CURVE('E353',#830,#795,#836,.T.);
#838=ORIENTED_EDGE('',*,*,#837,.T.);
#839=ORIENTED_EDGE('',*,*,#796,.T.);
#840=EDGE_LOOP('',(#815,#816,#824,#832,#838,#839));
#841=FACE_BOUND('',#840,.T.);
#842=ADVANCED_FACE('F652',(#841),#814,.T.);
#843=CARTESIAN_POINT('',(8.,-4.,35.));
#844=DIRECTION('',(0.,-1.,0.));
#845=DIRECTION('',(0.,0.,-1.));
#846=AXIS2_PLACEMENT_3D('',#843,#844,#845);
#847=PLANE('',#846);
#848=CARTESIAN_POINT('',(0.,-4.,-30.));
#849=DIRECTION('',(0.,1.,0.));
#850=DIRECTION('',(0.,0.,1.));
#851=AXIS2_PLACEMENT_3D('',#848,#849,#850);
#852=CIRCLE('',#851,2.5);
#853=CARTESIAN_POINT('',(0.,-4.,-27.5));
#854=VERTEX_POINT('',#853);
#855=EDGE_CURVE('E1020',#854,#854,#852,.T.);
#856=ORIENTED_EDGE('',*,*,#855,.T.);
#857=EDGE_LOOP('',(#856));
#858=FACE_BOUND('',#857,.T.);
#859=CARTESIAN_POINT('',(0.,-4.,-10.));
#860=DIRECTION('',(0.,1.,0.));
#861=DIRECTION('',(0.,0.,1.));
#862=AXIS2_PLACEMENT_3D('',#859,#860,#861);
#863=CIRCLE('',#862,2.5);
#864=CARTESIAN_POINT('',(0.,-4.,-7.5));
#865=VERTEX_POINT('',#864);
#866=EDGE_CURVE('E1026',#865,#865,#863,.T.);
#867=ORIENTED_EDGE('',*,*,#866,.T.);
#868=EDGE_LOOP('',(#867));
#869=FACE_BOUND('',#868,.T.);
#870=CARTESIAN_POINT('',(0.,-4.,6.00000000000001));
#871=DIRECTION('',(0.,1.,0.));
#872=DIRECTION('',(0.,0.,1.));
#873=AXIS2_PLACEMENT_3D('',#870,#871,#872);
#874=CIRCLE('',#873,2.5);
#875=CARTESIAN_POINT('',(0.,-4.,8.50000000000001));
#876=VERTEX_POINT('',#875);
#877=EDGE_CURVE('E1032',#876,#876,#874,.T.);
#878=ORIENTED_EDGE('',*,*,#877,.T.);
#879=EDGE_LOOP('',(#878));
#880=FACE_BOUND('',#879,.T.);
#881=CARTESIAN_POINT('',(0.,-4.,26.));
#882=DIRECTION('',(0.,1.,0.));
#883=DIRECTION('',(0.,0.,1.));
#884=AXIS2_PLACEMENT_3D('',#881,#882,#883);
#885=CIRCLE('',#884,2.5);
#886=CARTESIAN_POINT('',(0.,-4.,28.5));
#887=VERTEX_POINT('',#886);
#888=EDGE_CURVE('E269',#887,#887,#885,.T.);
#889=ORIENTED_EDGE('',*,*,#888,.T.);
#890=EDGE_LOOP('',(#889));
#891=FACE_BOUND('',#890,.T.);
#892=ORIENTED_EDGE('',*,*,#837,.F.);
#893=DIRECTION('',(-1.,0.,0.));
#894=VECTOR('',#893,1.);
#895=CARTESIAN_POINT('',(-8.,-4.,-40.));
#896=LINE('',#895,#894);
#897=EDGE_CURVE('E347',#744,#830,#896,.T.);
#898=ORIENTED_EDGE('',*,*,#897,.F.);
#899=ORIENTED_EDGE('',*,*,#745,.F.);
#900=ORIENTED_EDGE('',*,*,#778,.F.);
#901=ORIENTED_EDGE('',*,*,#702,.F.);
#902=ORIENTED_EDGE('',*,*,#803,.F.);
#903=EDGE_LOOP('',(#892,#898,#899,#900,#901,#902));
#904=FACE_BOUND('',#903,.T.);
#905=ADVANCED_FACE('F657',(#858,#869,#880,#891,#904),#847,.T.);
#906=CARTESIAN_POINT('',(-8.,0.,-40.));
#907=DIRECTION('',(0.,-1.,0.));
#908=DIRECTION('',(0.,0.,-1.));
#909=AXIS2_PLACEMENT_3D('',#906,#907,#908);
#910=PLANE('',#909);
#911=CARTESIAN_POINT('',(0.,0.,-30.));
#912=DIRECTION('',(0.,1.,0.));
#913=DIRECTION('',(0.,0.,1.));
#914=AXIS2_PLACEMENT_3D('',#911,#912,#913);
#915=CIRCLE('',#914,2.5);
#916=CARTESIAN_POINT('',(0.,0.,-27.5));
#917=VERTEX_POINT('',#916);
#918=EDGE_CURVE('E1018',#917,#917,#915,.T.);
#919=ORIENTED_EDGE('',*,*,#918,.F.);
#920=EDGE_LOOP('',(#919));
#921=FACE_BOUND('',#920,.T.);
#922=CARTESIAN_POINT('',(0.,0.,-10.));
#923=DIRECTION('',(0.,1.,0.));
#924=DIRECTION('',(0.,0.,1.));
#925=AXIS2_PLACEMENT_3D('',#922,#923,#924);
#926=CIRCLE('',#925,2.5);
#927=CARTESIAN_POINT('',(0.,0.,-7.5));
#928=VERTEX_POINT('',#927);
#929=EDGE_CURVE('E1023',#928,#928,#926,.T.);
#930=ORIENTED_EDGE('',*,*,#929,.F.);
#931=EDGE_LOOP('',(#930));
#932=FACE_BOUND('',#931,.T.);
#933=ORIENTED_EDGE('',*,*,#32,.T.);
#934=ORIENTED_EDGE('',*,*,#759,.F.);
#935=DIRECTION('',(1.,0.,0.));
#936=VECTOR('',#935,1.);
#937=CARTESIAN_POINT('',(-8.,0.,-40.));
#938=LINE('',#937,#936);
#939=EDGE_CURVE('E342',#822,#752,#938,.T.);
#940=ORIENTED_EDGE('',*,*,#939,.F.);
#941=ORIENTED_EDGE('',*,*,#823,.T.);
#942=EDGE_LOOP('',(#933,#934,#940,#941));
#943=FACE_BOUND('',#942,.T.);
#944=ADVANCED_FACE('F786',(#921,#932,#943),#910,.F.);
#945=CARTESIAN_POINT('',(0.,0.,-40.));
#946=DIRECTION('',(0.,0.,-1.));
#947=DIRECTION('',(-1.,0.,0.));
#948=AXIS2_PLACEMENT_3D('',#945,#946,#947);
#949=PLANE('',#948);
#950=ORIENTED_EDGE('',*,*,#831,.T.);
#951=ORIENTED_EDGE('',*,*,#939,.T.);
#952=ORIENTED_EDGE('',*,*,#753,.T.);
#953=ORIENTED_EDGE('',*,*,#897,.T.);
#954=EDGE_LOOP('',(#950,#951,#952,#953));
#955=FACE_BOUND('',#954,.T.);
#956=ADVANCED_FACE('F661',(#955),#949,.T.);
#957=CARTESIAN_POINT('',(7.5,-4.,137.));
#958=DIRECTION('',(0.,1.,0.));
#959=DIRECTION('',(0.,0.,1.));
#960=AXIS2_PLACEMENT_3D('',#957,#958,#959);
#961=CYLINDRICAL_SURFACE('',#960,1.5);
#962=ORIENTED_EDGE('',*,*,#143,.F.);
#963=DIRECTION('',(0.,1.,0.));
#964=VECTOR('',#963,1.);
#965=CARTESIAN_POINT('',(6.,-4.,137.));
#966=LINE('',#965,#964);
#967=CARTESIAN_POINT('',(6.,0.,137.));
#968=VERTEX_POINT('',#967);
#969=EDGE_CURVE('E302',#133,#968,#966,.T.);
#970=ORIENTED_EDGE('',*,*,#969,.T.);
#971=CARTESIAN_POINT('',(7.5,0.,137.));
#972=DIRECTION('',(0.,-1.,0.));
#973=DIRECTION('',(1.,0.,0.));
#974=AXIS2_PLACEMENT_3D('',#971,#972,#973);
#975=CIRCLE('',#974,1.5);
#976=CARTESIAN_POINT('',(7.5,0.,135.5));
#977=VERTEX_POINT('',#976);
#978=EDGE_CURVE('E300',#977,#968,#975,.F.);
#979=ORIENTED_EDGE('',*,*,#978,.F.);
#980=DIRECTION('',(0.,1.,0.));
#981=VECTOR('',#980,1.);
#982=CARTESIAN_POINT('',(7.5,-4.,135.5));
#983=LINE('',#982,#981);
#984=EDGE_CURVE('E311',#977,#142,#983,.F.);
#985=ORIENTED_EDGE('',*,*,#984,.T.);
#986=EDGE_LOOP('',(#962,#970,#979,#985));
#987=FACE_BOUND('',#986,.T.);
#988=ORIENTED_EDGE('',*,*,#262,.T.);
#989=EDGE_LOOP('',(#988));
#990=FACE_BOUND('',#989,.T.);
#991=ADVANCED_FACE('F413',(#987,#990),#961,.F.);
#992=CARTESIAN_POINT('',(7.5,-4.,107.));
#993=DIRECTION('',(0.,1.,0.));
#994=DIRECTION('',(0.,0.,1.));
#995=AXIS2_PLACEMENT_3D('',#992,#993,#994);
#996=CYLINDRICAL_SURFACE('',#995,1.5);
#997=ORIENTED_EDGE('',*,*,#160,.F.);
#998=DIRECTION('',(0.,1.,0.));
#999=VECTOR('',#998,1.);
#1000=CARTESIAN_POINT('',(7.5,-4.,108.5));
#1001=LINE('',#1000,#999);
#1002=CARTESIAN_POINT('',(7.5,0.,108.5));
#1003=VERTEX_POINT('',#1002);
#1004=EDGE_CURVE('E11',#150,#1003,#1001,.T.);
#1005=ORIENTED_EDGE('',*,*,#1004,.T.);
#1006=CARTESIAN_POINT('',(7.5,0.,107.));
#1007=DIRECTION('',(0.,-1.,0.));
#1008=DIRECTION('',(1.,0.,0.));
#1009=AXIS2_PLACEMENT_3D('',#1006,#1007,#1008);
#1010=CIRCLE('',#1009,1.5);
#1011=CARTESIAN_POINT('',(6.,0.,107.));
#1012=VERTEX_POINT('',#1011);
#1013=EDGE_CURVE('E298',#1012,#1003,#1010,.F.);
#1014=ORIENTED_EDGE('',*,*,#1013,.F.);
#1015=DIRECTION('',(0.,1.,0.));
#1016=VECTOR('',#1015,1.);
#1017=CARTESIAN_POINT('',(6.,-4.,107.));
#1018=LINE('',#1017,#1016);
#1019=EDGE_CURVE('E308',#1012,#159,#1018,.F.);
#1020=ORIENTED_EDGE('',*,*,#1019,.T.);
#1021=EDGE_LOOP('',(#997,#1005,#1014,#1020));
#1022=FACE_BOUND('',#1021,.T.);
#1023=ORIENTED_EDGE('',*,*,#251,.T.);
#1024=EDGE_LOOP('',(#1023));
#1025=FACE_BOUND('',#1024,.T.);
#1026=ADVANCED_FACE('F396',(#1022,#1025),#996,.F.);
#1027=CARTESIAN_POINT('',(-7.49999999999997,-4.,107.));
#1028=DIRECTION('',(0.,1.,0.));
#1029=DIRECTION('',(0.,0.,1.));
#1030=AXIS2_PLACEMENT_3D('',#1027,#1028,#1029);
#1031=CYLINDRICAL_SURFACE('',#1030,1.5);
#1032=ORIENTED_EDGE('',*,*,#353,.T.);
#1033=EDGE_LOOP('',(#1032));
#1034=FACE_BOUND('',#1033,.T.);
#1035=CARTESIAN_POINT('',(-7.49999999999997,0.,107.));
#1036=DIRECTION('',(0.,-1.,0.));
#1037=DIRECTION('',(1.,0.,0.));
#1038=AXIS2_PLACEMENT_3D('',#1035,#1036,#1037);
#1039=CIRCLE('',#1038,1.5);
#1040=CARTESIAN_POINT('',(-7.5,0.,108.5));
#1041=VERTEX_POINT('',#1040);
#1042=CARTESIAN_POINT('',(-5.99999999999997,0.,107.));
#1043=VERTEX_POINT('',#1042);
#1044=EDGE_CURVE('E290',#1041,#1043,#1039,.F.);
#1045=ORIENTED_EDGE('',*,*,#1044,.F.);
#1046=DIRECTION('',(0.,1.,0.));
#1047=VECTOR('',#1046,1.);
#1048=CARTESIAN_POINT('',(-7.5,-4.,108.5));
#1049=LINE('',#1048,#1047);
#1050=EDGE_CURVE('E305',#1041,#108,#1049,.F.);
#1051=ORIENTED_EDGE('',*,*,#1050,.T.);
#1052=ORIENTED_EDGE('',*,*,#109,.F.);
#1053=DIRECTION('',(0.,1.,0.));
#1054=VECTOR('',#1053,1.);
#1055=CARTESIAN_POINT('',(-5.99999999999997,-4.,107.));
#1056=LINE('',#1055,#1054);
#1057=EDGE_CURVE('E41',#106,#1043,#1056,.T.);
#1058=ORIENTED_EDGE('',*,*,#1057,.T.);
#1059=EDGE_LOOP('',(#1045,#1051,#1052,#1058));
#1060=FACE_BOUND('',#1059,.T.);
#1061=ADVANCED_FACE('F384',(#1034,#1060),#1031,.F.);
#1062=CARTESIAN_POINT('',(-7.5,-4.,137.));
#1063=DIRECTION('',(0.,1.,0.));
#1064=DIRECTION('',(0.,0.,1.));
#1065=AXIS2_PLACEMENT_3D('',#1062,#1063,#1064);
#1066=CYLINDRICAL_SURFACE('',#1065,1.5);
#1067=ORIENTED_EDGE('',*,*,#126,.F.);
#1068=DIRECTION('',(0.,1.,0.));
#1069=VECTOR('',#1068,1.);
#1070=CARTESIAN_POINT('',(-7.5,-4.,135.5));
#1071=LINE('',#1070,#1069);
#1072=CARTESIAN_POINT('',(-7.5,0.,135.5));
#1073=VERTEX_POINT('',#1072);
#1074=EDGE_CURVE('E378',#116,#1073,#1071,.T.);
#1075=ORIENTED_EDGE('',*,*,#1074,.T.);
#1076=CARTESIAN_POINT('',(-7.5,0.,137.));
#1077=DIRECTION('',(0.,-1.,0.));
#1078=DIRECTION('',(1.,0.,0.));
#1079=AXIS2_PLACEMENT_3D('',#1076,#1077,#1078);
#1080=CIRCLE('',#1079,1.5);
#1081=CARTESIAN_POINT('',(-6.,0.,137.));
#1082=VERTEX_POINT('',#1081);
#1083=EDGE_CURVE('E372',#1082,#1073,#1080,.F.);
#1084=ORIENTED_EDGE('',*,*,#1083,.F.);
#1085=DIRECTION('',(0.,1.,0.));
#1086=VECTOR('',#1085,1.);
#1087=CARTESIAN_POINT('',(-6.,-4.,137.));
#1088=LINE('',#1087,#1086);
#1089=EDGE_CURVE('E374',#1082,#125,#1088,.F.);
#1090=ORIENTED_EDGE('',*,*,#1089,.T.);
#1091=EDGE_LOOP('',(#1067,#1075,#1084,#1090));
#1092=FACE_BOUND('',#1091,.T.);
#1093=ORIENTED_EDGE('',*,*,#342,.T.);
#1094=EDGE_LOOP('',(#1093));
#1095=FACE_BOUND('',#1094,.T.);
#1096=ADVANCED_FACE('F407',(#1092,#1095),#1066,.F.);
#1097=CARTESIAN_POINT('',(7.5,0.,137.));
#1098=DIRECTION('',(1.,0.,0.));
#1099=DIRECTION('',(0.,1.,0.));
#1100=AXIS2_PLACEMENT_3D('',#1097,#1098,#1099);
#1101=PLANE('',#1100);
#1102=DIRECTION('',(0.,0.,1.));
#1103=VECTOR('',#1102,1.);
#1104=CARTESIAN_POINT('',(7.5,0.,137.));
#1105=LINE('',#1104,#1103);
#1106=EDGE_CURVE('E286',#1003,#977,#1105,.T.);
#1107=ORIENTED_EDGE('',*,*,#1106,.F.);
#1108=ORIENTED_EDGE('',*,*,#1004,.F.);
#1109=ORIENTED_EDGE('',*,*,#151,.T.);
#1110=ORIENTED_EDGE('',*,*,#984,.F.);
#1111=EDGE_LOOP('',(#1107,#1108,#1109,#1110));
#1112=FACE_BOUND('',#1111,.T.);
#1113=ADVANCED_FACE('F417',(#1112),#1101,.F.);
#1114=CARTESIAN_POINT('',(-7.5,0.,107.));
#1115=DIRECTION('',(0.,0.,-1.));
#1116=DIRECTION('',(-1.,0.,0.));
#1117=AXIS2_PLACEMENT_3D('',#1114,#1115,#1116);
#1118=PLANE('',#1117);
#1119=DIRECTION('',(1.,0.,0.));
#1120=VECTOR('',#1119,1.);
#1121=CARTESIAN_POINT('',(-7.5,0.,107.));
#1122=LINE('',#1121,#1120);
#1123=EDGE_CURVE('E282',#1043,#1012,#1122,.T.);
#1124=ORIENTED_EDGE('',*,*,#1123,.F.);
#1125=ORIENTED_EDGE('',*,*,#1057,.F.);
#1126=ORIENTED_EDGE('',*,*,#166,.T.);
#1127=ORIENTED_EDGE('',*,*,#1019,.F.);
#1128=EDGE_LOOP('',(#1124,#1125,#1126,#1127));
#1129=FACE_BOUND('',#1128,.T.);
#1130=ADVANCED_FACE('F388',(#1129),#1118,.F.);
#1131=CARTESIAN_POINT('',(-7.5,0.,137.));
#1132=DIRECTION('',(-1.,0.,0.));
#1133=DIRECTION('',(0.,-1.,0.));
#1134=AXIS2_PLACEMENT_3D('',#1131,#1132,#1133);
#1135=PLANE('',#1134);
#1136=DIRECTION('',(0.,0.,-1.));
#1137=VECTOR('',#1136,1.);
#1138=CARTESIAN_POINT('',(-7.5,0.,137.));
#1139=LINE('',#1138,#1137);
#1140=EDGE_CURVE('E279',#1073,#1041,#1139,.T.);
#1141=ORIENTED_EDGE('',*,*,#1140,.F.);
#1142=ORIENTED_EDGE('',*,*,#1074,.F.);
#1143=ORIENTED_EDGE('',*,*,#117,.T.);
#1144=ORIENTED_EDGE('',*,*,#1050,.F.);
#1145=EDGE_LOOP('',(#1141,#1142,#1143,#1144));
#1146=FACE_BOUND('',#1145,.T.);
#1147=ADVANCED_FACE('F404',(#1146),#1135,.F.);
#1148=CARTESIAN_POINT('',(-7.5,0.,137.));
#1149=DIRECTION('',(0.,0.,1.));
#1150=DIRECTION('',(1.,0.,0.));
#1151=AXIS2_PLACEMENT_3D('',#1148,#1149,#1150);
#1152=PLANE('',#1151);
#1153=ORIENTED_EDGE('',*,*,#134,.T.);
#1154=ORIENTED_EDGE('',*,*,#1089,.F.);
#1155=DIRECTION('',(-1.,0.,0.));
#1156=VECTOR('',#1155,1.);
#1157=CARTESIAN_POINT('',(-7.5,0.,137.));
#1158=LINE('',#1157,#1156);
#1159=EDGE_CURVE('E56',#968,#1082,#1158,.T.);
#1160=ORIENTED_EDGE('',*,*,#1159,.F.);
#1161=ORIENTED_EDGE('',*,*,#969,.F.);
#1162=EDGE_LOOP('',(#1153,#1154,#1160,#1161));
#1163=FACE_BOUND('',#1162,.T.);
#1164=ADVANCED_FACE('F418',(#1163),#1152,.F.);
#1165=CARTESIAN_POINT('',(0.,0.,0.));
#1166=DIRECTION('',(0.,-1.,0.));
#1167=DIRECTION('',(1.,0.,0.));
#1168=AXIS2_PLACEMENT_3D('',#1165,#1166,#1167);
#1169=PLANE('',#1168);
#1170=ORIENTED_EDGE('',*,*,#978,.T.);
#1171=ORIENTED_EDGE('',*,*,#1159,.T.);
#1172=ORIENTED_EDGE('',*,*,#1083,.T.);
#1173=ORIENTED_EDGE('',*,*,#1140,.T.);
#1174=ORIENTED_EDGE('',*,*,#1044,.T.);
#1175=ORIENTED_EDGE('',*,*,#1123,.T.);
#1176=ORIENTED_EDGE('',*,*,#1013,.T.);
#1177=ORIENTED_EDGE('',*,*,#1106,.T.);
#1178=EDGE_LOOP('',(#1170,#1171,#1172,#1173,#1174,#1175,#1176,#1177));
#1179=FACE_BOUND('',#1178,.T.);
#1180=ADVANCED_FACE('F399',(#1179),#1169,.T.);
#1181=CARTESIAN_POINT('',(0.,0.,79.));
#1182=DIRECTION('',(0.,-1.,0.));
#1183=DIRECTION('',(1.,0.,0.));
#1184=AXIS2_PLACEMENT_3D('',#1181,#1182,#1183);
#1185=CYLINDRICAL_SURFACE('',#1184,3.);
#1186=ORIENTED_EDGE('',*,*,#81,.T.);
#1187=DIRECTION('',(0.,-1.,0.));
#1188=VECTOR('',#1187,1.);
#1189=CARTESIAN_POINT('',(-3.,0.,79.));
#1190=LINE('',#1189,#1188);
#1191=CARTESIAN_POINT('',(-3.,0.,79.));
#1192=VERTEX_POINT('',#1191);
#1193=EDGE_CURVE('E234',#1192,#69,#1190,.T.);
#1194=ORIENTED_EDGE('',*,*,#1193,.F.);
#1195=CARTESIAN_POINT('',(0.,0.,79.));
#1196=DIRECTION('',(0.,-1.,0.));
#1197=DIRECTION('',(1.,0.,0.));
#1198=AXIS2_PLACEMENT_3D('',#1195,#1196,#1197);
#1199=CIRCLE('',#1198,3.);
#1200=CARTESIAN_POINT('',(3.,0.,79.));
#1201=VERTEX_POINT('',#1200);
#1202=EDGE_CURVE('E238',#1201,#1192,#1199,.T.);
#1203=ORIENTED_EDGE('',*,*,#1202,.F.);
#1204=DIRECTION('',(0.,-1.,0.));
#1205=VECTOR('',#1204,1.);
#1206=CARTESIAN_POINT('',(3.,0.,79.));
#1207=LINE('',#1206,#1205);
#1208=EDGE_CURVE('E273',#1201,#80,#1207,.T.);
#1209=ORIENTED_EDGE('',*,*,#1208,.T.);
#1210=EDGE_LOOP('',(#1186,#1194,#1203,#1209));
#1211=FACE_BOUND('',#1210,.T.);
#1212=ADVANCED_FACE('F236',(#1211),#1185,.F.);
#1213=CARTESIAN_POINT('',(3.,0.,79.));
#1214=DIRECTION('',(1.,0.,0.));
#1215=DIRECTION('',(0.,1.,0.));
#1216=AXIS2_PLACEMENT_3D('',#1213,#1214,#1215);
#1217=PLANE('',#1216);
#1218=ORIENTED_EDGE('',*,*,#89,.T.);
#1219=ORIENTED_EDGE('',*,*,#1208,.F.);
#1220=DIRECTION('',(0.,0.,1.));
#1221=VECTOR('',#1220,1.);
#1222=CARTESIAN_POINT('',(3.,0.,79.));
#1223=LINE('',#1222,#1221);
#1224=CARTESIAN_POINT('',(3.,0.,65.));
#1225=VERTEX_POINT('',#1224);
#1226=EDGE_CURVE('E244',#1225,#1201,#1223,.T.);
#1227=ORIENTED_EDGE('',*,*,#1226,.F.);
#1228=DIRECTION('',(0.,-1.,0.));
#1229=VECTOR('',#1228,1.);
#1230=CARTESIAN_POINT('',(3.,0.,65.));
#1231=LINE('',#1230,#1229);
#1232=EDGE_CURVE('E276',#1225,#88,#1231,.T.);
#1233=ORIENTED_EDGE('',*,*,#1232,.T.);
#1234=EDGE_LOOP('',(#1218,#1219,#1227,#1233));
#1235=FACE_BOUND('',#1234,.T.);
#1236=ADVANCED_FACE('F867',(#1235),#1217,.F.);
#1237=CARTESIAN_POINT('',(0.,0.,65.));
#1238=DIRECTION('',(0.,-1.,0.));
#1239=DIRECTION('',(1.,0.,0.));
#1240=AXIS2_PLACEMENT_3D('',#1237,#1238,#1239);
#1241=CYLINDRICAL_SURFACE('',#1240,3.);
#1242=ORIENTED_EDGE('',*,*,#96,.T.);
#1243=ORIENTED_EDGE('',*,*,#1232,.F.);
#1244=CARTESIAN_POINT('',(0.,0.,65.));
#1245=DIRECTION('',(0.,-1.,0.));
#1246=DIRECTION('',(1.,0.,0.));
#1247=AXIS2_PLACEMENT_3D('',#1244,#1245,#1246);
#1248=CIRCLE('',#1247,3.);
#1249=CARTESIAN_POINT('',(-3.,0.,65.));
#1250=VERTEX_POINT('',#1249);
#1251=EDGE_CURVE('E252',#1250,#1225,#1248,.T.);
#1252=ORIENTED_EDGE('',*,*,#1251,.F.);
#1253=DIRECTION('',(0.,-1.,0.));
#1254=VECTOR('',#1253,1.);
#1255=CARTESIAN_POINT('',(-3.,0.,65.));
#1256=LINE('',#1255,#1254);
#1257=EDGE_CURVE('E243',#1250,#71,#1256,.T.);
#1258=ORIENTED_EDGE('',*,*,#1257,.T.);
#1259=EDGE_LOOP('',(#1242,#1243,#1252,#1258));
#1260=FACE_BOUND('',#1259,.T.);
#1261=ADVANCED_FACE('F876',(#1260),#1241,.F.);
#1262=CARTESIAN_POINT('',(-3.,0.,79.));
#1263=DIRECTION('',(-1.,0.,0.));
#1264=DIRECTION('',(0.,-1.,0.));
#1265=AXIS2_PLACEMENT_3D('',#1262,#1263,#1264);
#1266=PLANE('',#1265);
#1267=ORIENTED_EDGE('',*,*,#72,.T.);
#1268=ORIENTED_EDGE('',*,*,#1257,.F.);
#1269=DIRECTION('',(0.,0.,-1.));
#1270=VECTOR('',#1269,1.);
#1271=CARTESIAN_POINT('',(-3.,0.,79.));
#1272=LINE('',#1271,#1270);
#1273=EDGE_CURVE('E247',#1192,#1250,#1272,.T.);
#1274=ORIENTED_EDGE('',*,*,#1273,.F.);
#1275=ORIENTED_EDGE('',*,*,#1193,.T.);
#1276=EDGE_LOOP('',(#1267,#1268,#1274,#1275));
#1277=FACE_BOUND('',#1276,.T.);
#1278=ADVANCED_FACE('F248',(#1277),#1266,.F.);
#1279=CARTESIAN_POINT('',(0.,0.,79.));
#1280=DIRECTION('',(0.,-1.,0.));
#1281=DIRECTION('',(1.,0.,0.));
#1282=AXIS2_PLACEMENT_3D('',#1279,#1280,#1281);
#1283=PLANE('',#1282);
#1284=ORIENTED_EDGE('',*,*,#1202,.T.);
#1285=ORIENTED_EDGE('',*,*,#1273,.T.);
#1286=ORIENTED_EDGE('',*,*,#1251,.T.);
#1287=ORIENTED_EDGE('',*,*,#1226,.T.);
#1288=EDGE_LOOP('',(#1284,#1285,#1286,#1287));
#1289=FACE_BOUND('',#1288,.T.);
#1290=ADVANCED_FACE('F254',(#1289),#1283,.T.);
#1291=CARTESIAN_POINT('',(0.,-4.,26.));
#1292=DIRECTION('',(0.,1.,0.));
#1293=DIRECTION('',(0.,0.,1.));
#1294=AXIS2_PLACEMENT_3D('',#1291,#1292,#1293);
#1295=CYLINDRICAL_SURFACE('',#1294,2.5);
#1296=ORIENTED_EDGE('',*,*,#888,.F.);
#1297=EDGE_LOOP('',(#1296));
#1298=FACE_BOUND('',#1297,.T.);
#1299=ORIENTED_EDGE('',*,*,#608,.T.);
#1300=EDGE_LOOP('',(#1299));
#1301=FACE_BOUND('',#1300,.T.);
#1302=ADVANCED_FACE('F902',(#1298,#1301),#1295,.F.);
#1303=CARTESIAN_POINT('',(0.,-4.,6.00000000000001));
#1304=DIRECTION('',(0.,1.,0.));
#1305=DIRECTION('',(0.,0.,1.));
#1306=AXIS2_PLACEMENT_3D('',#1303,#1304,#1305);
#1307=CYLINDRICAL_SURFACE('',#1306,2.5);
#1308=ORIENTED_EDGE('',*,*,#877,.F.);
#1309=EDGE_LOOP('',(#1308));
#1310=FACE_BOUND('',#1309,.T.);
#1311=ORIENTED_EDGE('',*,*,#597,.T.);
#1312=EDGE_LOOP('',(#1311));
#1313=FACE_BOUND('',#1312,.T.);
#1314=ADVANCED_FACE('F914',(#1310,#1313),#1307,.F.);
#1315=CARTESIAN_POINT('',(0.,-4.,-10.));
#1316=DIRECTION('',(0.,1.,0.));
#1317=DIRECTION('',(0.,0.,1.));
#1318=AXIS2_PLACEMENT_3D('',#1315,#1316,#1317);
#1319=CYLINDRICAL_SURFACE('',#1318,2.5);
#1320=ORIENTED_EDGE('',*,*,#866,.F.);
#1321=EDGE_LOOP('',(#1320));
#1322=FACE_BOUND('',#1321,.T.);
#1323=ORIENTED_EDGE('',*,*,#929,.T.);
#1324=EDGE_LOOP('',(#1323));
#1325=FACE_BOUND('',#1324,.T.);
#1326=ADVANCED_FACE('F924',(#1322,#1325),#1319,.F.);
#1327=CARTESIAN_POINT('',(0.,-4.,-30.));
#1328=DIRECTION('',(0.,1.,0.));
#1329=DIRECTION('',(0.,0.,1.));
#1330=AXIS2_PLACEMENT_3D('',#1327,#1328,#1329);
#1331=CYLINDRICAL_SURFACE('',#1330,2.5);
#1332=ORIENTED_EDGE('',*,*,#855,.F.);
#1333=EDGE_LOOP('',(#1332));
#1334=FACE_BOUND('',#1333,.T.);
#1335=ORIENTED_EDGE('',*,*,#918,.T.);
#1336=EDGE_LOOP('',(#1335));
#1337=FACE_BOUND('',#1336,.T.);
#1338=ADVANCED_FACE('F944',(#1334,#1337),#1331,.F.);
#1339=CARTESIAN_POINT('',(-5.,2.,119.9));
#1340=DIRECTION('',(1.,0.,0.));
#1341=DIRECTION('',(0.,0.,-1.));
#1342=AXIS2_PLACEMENT_3D('',#1339,#1340,#1341);
#1343=CYLINDRICAL_SURFACE('',#1342,1.5);
#1344=CARTESIAN_POINT('',(-5.,2.,119.9));
#1345=DIRECTION('',(1.,0.,0.));
#1346=DIRECTION('',(0.,0.,-1.));
#1347=AXIS2_PLACEMENT_3D('',#1344,#1345,#1346);
#1348=CIRCLE('',#1347,1.5);
#1349=CARTESIAN_POINT('',(-5.,2.,118.4));
#1350=VERTEX_POINT('',#1349);
#1351=EDGE_CURVE('E1012',#1350,#1350,#1348,.T.);
#1352=ORIENTED_EDGE('',*,*,#1351,.F.);
#1353=EDGE_LOOP('',(#1352));
#1354=FACE_BOUND('',#1353,.T.);
#1355=ORIENTED_EDGE('',*,*,#314,.T.);
#1356=EDGE_LOOP('',(#1355));
#1357=FACE_BOUND('',#1356,.T.);
#1358=ADVANCED_FACE('F953',(#1354,#1357),#1343,.F.);
#1359=CARTESIAN_POINT('',(-5.,2.,119.9));
#1360=DIRECTION('',(1.,0.,0.));
#1361=DIRECTION('',(0.,0.,-1.));
#1362=AXIS2_PLACEMENT_3D('',#1359,#1360,#1361);
#1363=PLANE('',#1362);
#1364=ORIENTED_EDGE('',*,*,#1351,.T.);
#1365=EDGE_LOOP('',(#1364));
#1366=FACE_BOUND('',#1365,.T.);
#1367=ADVANCED_FACE('F966',(#1366),#1363,.T.);
#1368=CARTESIAN_POINT('',(-7.,2.,10.9));
#1369=DIRECTION('',(1.,0.,0.));
#1370=DIRECTION('',(0.,0.,-1.));
#1371=AXIS2_PLACEMENT_3D('',#1368,#1369,#1370);
#1372=CYLINDRICAL_SURFACE('',#1371,1.5);
#1373=CARTESIAN_POINT('',(-7.,2.,10.9));
#1374=DIRECTION('',(1.,0.,0.));
#1375=DIRECTION('',(0.,0.,-1.));
#1376=AXIS2_PLACEMENT_3D('',#1373,#1374,#1375);
#1377=CIRCLE('',#1376,1.5);
#1378=CARTESIAN_POINT('',(-7.,2.,9.40000000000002));
#1379=VERTEX_POINT('',#1378);
#1380=EDGE_CURVE('E1007',#1379,#1379,#1377,.T.);
#1381=ORIENTED_EDGE('',*,*,#1380,.F.);
#1382=EDGE_LOOP('',(#1381));
#1383=FACE_BOUND('',#1382,.T.);
#1384=ORIENTED_EDGE('',*,*,#726,.T.);
#1385=EDGE_LOOP('',(#1384));
#1386=FACE_BOUND('',#1385,.T.);
#1387=ADVANCED_FACE('F976',(#1383,#1386),#1372,.F.);
#1388=CARTESIAN_POINT('',(-7.,2.,10.9));
#1389=DIRECTION('',(1.,0.,0.));
#1390=DIRECTION('',(0.,0.,-1.));
#1391=AXIS2_PLACEMENT_3D('',#1388,#1389,#1390);
#1392=PLANE('',#1391);
#1393=ORIENTED_EDGE('',*,*,#1380,.T.);
#1394=EDGE_LOOP('',(#1393));
#1395=FACE_BOUND('',#1394,.T.);
#1396=ADVANCED_FACE('F991',(#1395),#1392,.T.);
#1397=CLOSED_SHELL('',(#58,#238,#301,#334,#388,#410,#429,#486,#498,#515,#567,#584,#648,#665,
#682,#713,#764,#783,#809,#842,#905,#944,#956,#991,#1026,#1061,#1096,#1113,#1130,#1147,#1164,
#1180,#1212,#1236,#1261,#1278,#1290,#1302,#1314,#1326,#1338,#1358,#1367,#1387,#1396));
#1398=MANIFOLD_SOLID_BREP('B2',#1397);
#1399=ADVANCED_BREP_SHAPE_REPRESENTATION('',(#18,#1398),#14);
#1400=SHAPE_DEFINITION_REPRESENTATION(#9,#1399);
ENDSEC;
END-ISO-10303-21;
